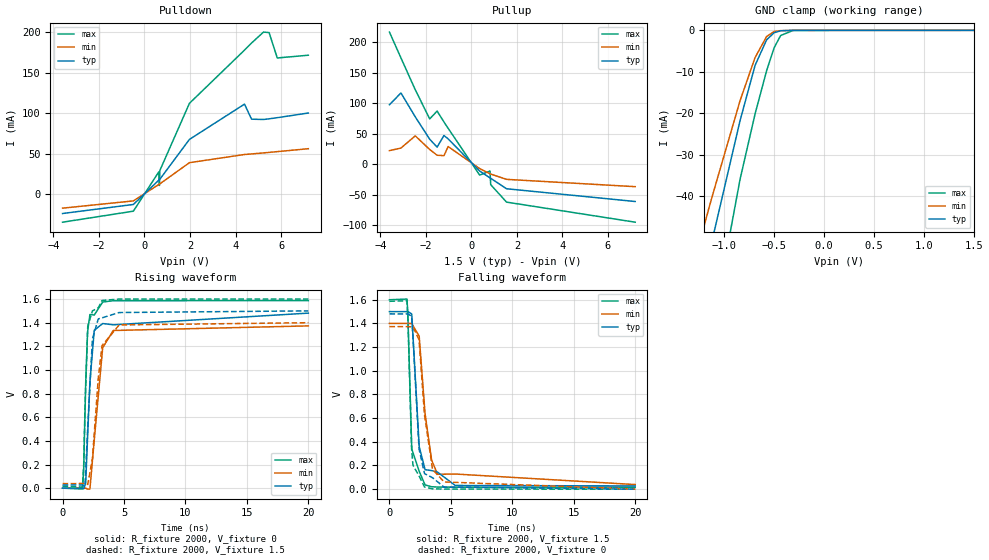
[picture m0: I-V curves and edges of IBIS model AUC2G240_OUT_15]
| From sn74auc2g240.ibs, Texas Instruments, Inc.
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[Model]   AUC2G240_OUT_15
Model_type  3-state
Enable   Active-Low
Vref =   0
Rref =   2000
Cref =   15p
Vmeas =   0.75
| variable   typ   min   max
C_comp   5.26pF   4.70pF   5.52pF
| C_pullup   4.79pF   0.02pF   13.20pF
| C_pulldown   6.36pF   5.33pF   12.83pF
| C_tri-state   5.26pF   4.70pF   5.52pF
[Temperature Range]   40   100   -40
| Ambient temperature   25   85   -40
[Voltage range]   1.5   1.4   1.6
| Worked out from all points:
|   slope of the pulldown table from 0 to 0.225 V, typ, clamps not added: 36.8 ohm
|   slope of the pullup table from 0 to 0.225 V, typ, clamps not added: 29.6 ohm
|   GND clamp passes 1 mA (typ) near -0.53 V on its own axis
|   rising waveform, R_fixture 2000, V_fixture 0: 20-80 % time 405ps typ, 635ps min, 253ps max; typ from 0 V to 1.48 V
|   falling waveform, R_fixture 2000, V_fixture 1.5: 20-80 % time 498ps typ, 792ps min, 273ps max; typ from 1.5 V to 0.027 V
|   rising waveform, R_fixture 2000, V_fixture 1.5: 20-80 % time 401ps typ, 627ps min, 250ps max; typ from 0.027 V to 1.5 V
|   falling waveform, R_fixture 2000, V_fixture 0: 20-80 % time 493ps typ, 779ps min, 271ps max; typ from 1.48 V to 0 V
[GND Clamp]
| AUC2G240_OUT_15
|   Voltage   I(typ)   I(min)   I(max)
-3.6V     -324.8mA   -272.6mA   -395.3mA
-1.51V    -93.07mA   -74.9mA    -123.7mA
-1.465V   -88.13mA   -70.8mA    -117.8mA
-1.33V    -73.37mA   -58.63mA   -100mA
-1.125V   -51.23mA   -40.54mA   -72.92mA
-840mV    -21.74mA   -16.94mA   -35.88mA
-690mV    -8.435mA   -6.553mA   -20.12mA
-575mV    -2.291mA   -1.489mA   -9.733mA
-500mV    -581.2uA   -306.5uA   -4.204mA
-435mV    -119.5uA   -65.92uA   -1.256mA
-310mV    -3.098uA   -2.805uA   -25.01uA
1.5V      385pA      7.758nA    372.5pA
[Pulldown]
| AUC2G240_OUT_15
|   Voltage   I(typ)   I(min)   I(max)
-3.6V     -23.87mA   -17.26mA   -34.61mA
-490mV    -12.71mA   -8.291mA   -20.99mA
630mV     17.4mA     12.02mA    27.68mA
655mV     18.03mA    12.44mA    10.77mA
675mV     18.52mA    12.77mA    29.29mA
1.975V    67.77mA    39mA       112.4mA
4.395V    111.4mA    49.1mA     178.2mA
4.705V    92.8mA     49.77mA    187mA
5.23V     92.39mA    51.08mA    200.5mA
5.475V    93.24mA    51.71mA    199.9mA
5.835V    94.64mA    52.66mA    168.5mA
7.2V      100.4mA    56.27mA    171.9mA
[Pullup]
| AUC2G240_OUT_15
|   Voltage   I(typ)   I(min)   I(max)
-3.6V     97.41mA    22.16mA    216.7mA
-3.095V   116.8mA    26.35mA    174.4mA
-2.465V   77.56mA    46.39mA    122mA
-1.83V    40.8mA     23.97mA    74.26mA
-1.505V   27.88mA    14.58mA    87.05mA
-1.205V   47.01mA    13.93mA    69.21mA
-1.02V    41.38mA    28.81mA    58.8mA
365mV     -11.31mA   -7.286mA   -18.05mA
820mV     -22.63mA   -15.87mA   -11.24mA
850mV     -23.26mA   -16.33mA   -33.73mA
1.545V    -40.41mA   -25mA      -62.34mA
7.2V      -61.35mA   -37.01mA   -95.3mA
[Ramp]
| AUC2G240_OUT_15
| variable   typ   min   max
dV/dt_r   0.90/4.10E-10   0.84/6.44E-10   0.96/2.55E-10
dV/dt_f   0.89/5.04E-10   0.82/7.95E-10   0.95/2.74E-10
R_load = 2000
[Rising Waveform]
| AUC2G240_OUT_15
R_fixture =   2000
C_fixture =   0
L_fixture =   0
V_fixture =   0
V_fixture_min = 0
V_fixture_max = 0
|   Time   V(typ)   V(min)   V(max)
0s        7.607nV    28.63nV    906.6pV
1.625ns   -359.9uV   463uV      -7.663mV
1.72ns    -6.097mV   596.9uV    166.8mV
1.885ns   45mV       -186.9uV   898.8mV
2.035ns   430.3mV    -8.654mV   1.322V
2.225ns   896.9mV    -8.164mV   1.469V
2.58ns    1.336V     407.6mV    1.465V
3.265ns   1.393V     1.188V     1.575V
4.125ns   1.382V     1.334V     1.586V
20ns      1.481V     1.373V     1.587V
[Falling Waveform]
| AUC2G240_OUT_15
R_fixture =   2000
C_fixture =   0
L_fixture =   0
V_fixture =   1.5
V_fixture_min = 1.4
V_fixture_max = 1.6
|   Time   V(typ)   V(min)   V(max)
0s        1.5V       1.4V       1.6V
1.43ns    1.5V       1.4V       1.606V
1.5ns     1.5V       1.4V       1.47V
1.815ns   1.48V      1.399V     339.7mV
2.42ns    361.6mV    1.293V     151.6mV
2.9ns     164.6mV    637mV      35.44mV
3.435ns   157.2mV    244.2mV    20.48mV
3.92ns    143.4mV    125.6mV    17.9mV
5.355ns   31.27mV    127.9mV    16.59mV
20ns      27.21mV    38.79mV    16.41mV
[Rising Waveform]
| AUC2G240_OUT_15
R_fixture =   2000
C_fixture =   0
L_fixture =   0
V_fixture =   1.5
V_fixture_min = 1.4
V_fixture_max = 1.6
|   Time   V(typ)   V(min)   V(max)
0s        27.17mV    38.77mV    16.4mV
1.625ns   26.8mV     39.15mV    9.101mV
1.72ns    21.75mV    39.23mV    195.8mV
1.82ns    21.42mV    39.23mV    661.1mV
2.05ns    522.3mV    30.77mV    1.37V
2.43ns    1.263V     251.1mV    1.5V
2.905ns   1.432V     929.5mV    1.526V
3.21ns    1.441V     1.206V     1.588V
4.605ns   1.486V     1.381V     1.6V
20ns      1.5V       1.4V       1.6V
[Falling Waveform]
| AUC2G240_OUT_15
R_fixture =   2000
C_fixture =   0
L_fixture =   0
V_fixture =   0
V_fixture_min = 0
V_fixture_max = 0
|   Time   V(typ)   V(min)   V(max)
0s        1.481V     1.373V     1.587V
1.43ns    1.48V      1.373V     1.592V
1.5ns     1.48V      1.373V     1.453V
1.805ns   1.461V     1.372V     338.9mV
1.915ns   1.283V     1.372V     201.4mV
2.41ns    338.9mV    1.261V     112mV
2.855ns   131.6mV    624.6mV    17.91mV
3.51ns    96.27mV    165.6mV    3.068mV
4.45ns    17.73mV    61.08mV    528.6uV
20ns      38.15uV    12.96uV    15.4uV
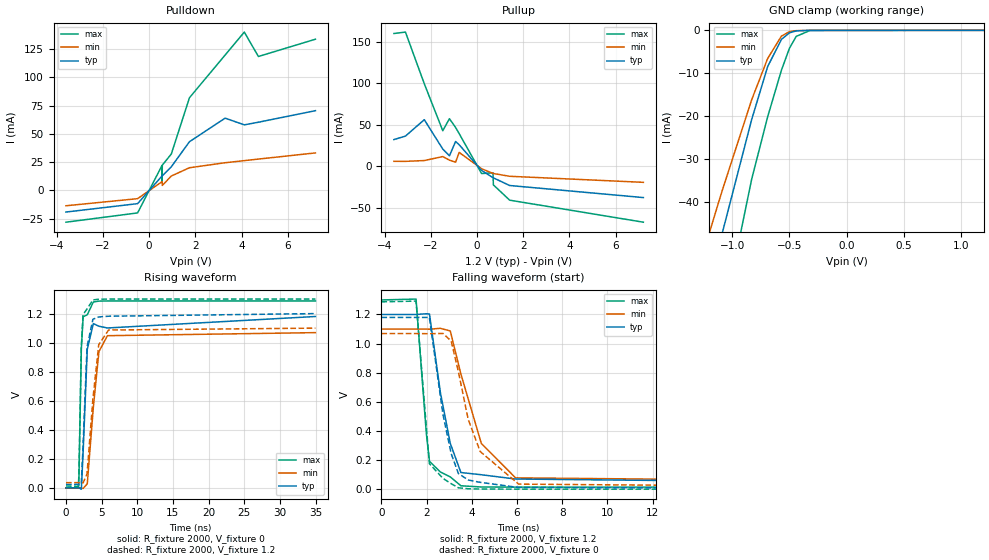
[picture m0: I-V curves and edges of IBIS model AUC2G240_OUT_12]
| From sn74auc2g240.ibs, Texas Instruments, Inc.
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[Model]   AUC2G240_OUT_12
Model_type  3-state
Enable   Active-Low
Vref =   0
Rref =   2000
Cref =   15p
Vmeas =   0.6
| variable   typ   min   max
C_comp   5.37pF   4.84pF   5.65pF
| C_pullup   4.52pF   0.82pF   9.79pF
| C_pulldown   6.19pF   5.48pF   8.81pF
| C_tri-state   5.37pF   4.84pF   5.65pF
[Temperature Range]   40   100   -40
| Ambient temperature   25   85   -40
[Voltage range]   1.2   1.1   1.3
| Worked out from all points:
|   slope of the pulldown table from 0 to 0.18 V, typ, clamps not added: 42.4 ohm
|   slope of the pullup table from 0 to 0.18 V, typ, clamps not added: 38.6 ohm
|   GND clamp passes 1 mA (typ) near -0.53 V on its own axis
|   rising waveform, R_fixture 2000, V_fixture 0: 20-80 % time 576ps typ, 1.04ns min, 320ps max; typ from 0 V to 1.18 V
|   falling waveform, R_fixture 2000, V_fixture 1.2: 20-80 % time 769ps typ, 1.25ns min, 386ps max; typ from 1.2 V to 0.024 V
|   rising waveform, R_fixture 2000, V_fixture 1.2: 20-80 % time 568ps typ, 1.03ns min, 314ps max; typ from 0.024 V to 1.2 V
|   falling waveform, R_fixture 2000, V_fixture 0: 20-80 % time 750ps typ, 1.19ns min, 381ps max; typ from 1.18 V to 0 V
[GND Clamp]
| AUC2G240_OUT_12
|   Voltage   I(typ)   I(min)   I(max)
-3.6V     -324.8mA   -272.6mA   -395.3mA
-1.455V   -87.03mA   -69.89mA   -116.5mA
-1.285V   -68.47mA   -54.61mA   -94.06mA
-1.12V    -50.69mA   -40.11mA   -72.26mA
-1.085V   -46.97mA   -37.09mA   -67.64mA
-830mV    -20.77mA   -16.17mA   -34.67mA
-690mV    -8.435mA   -6.553mA   -20.12mA
-570mV    -2.125mA   -1.36mA    -9.318mA
-500mV    -581.2uA   -306.5uA   -4.204mA
-440mV    -136.4uA   -74.2uA    -1.408mA
-320mV    -4.212uA   -3.691uA   -36.5uA
1.2V      309.5pA    7.675nA    266.7pA
[Pulldown]
| AUC2G240_OUT_12
|   Voltage   I(typ)   I(min)   I(max)
-3.6V     -19.18mA   -13.63mA   -28.17mA
-500mV    -11.75mA   -7.339mA   -19.96mA
545mV     12.46mA    7.541mA    21.58mA
550mV     12.55mA    7.59mA     7.985mA
560mV     12.73mA    7.686mA    8.172mA
570mV     12.91mA    4.373mA    22.34mA
960mV     20.87mA    12.69mA    32.2mA
1.745V    43.07mA    20.04mA    81.99mA
3.29V     63.92mA    24.45mA    119.8mA
4.12V     58mA       26.33mA    140.1mA
4.73V     60.31mA    27.69mA    118.5mA
7.2V      70.54mA    33.15mA    133.8mA
[Pullup]
| AUC2G240_OUT_12
|   Voltage   I(typ)   I(min)   I(max)
-3.6V     32.21mA    6.05mA     159.8mA
-3.1V     36.38mA    6.008mA    161.5mA
-2.285V   56.12mA    6.972mA    99.34mA
-1.485V   20.82mA    11.76mA    42.86mA
-1.195V   12.69mA    7.446mA    57.3mA
-930mV    29.91mA    5.035mA    46.79mA
-775mV    26.01mA    16.75mA    39.41mA
195mV     -4.924mA   -2.842mA   -8.652mA
690mV     -13.63mA   -8.496mA   -7.804mA
705mV     -13.8mA    -8.599mA   -22.25mA
1.41V     -23.04mA   -11.95mA   -40.67mA
7.2V      -37.56mA   -19.23mA   -67.17mA
[Ramp]
| AUC2G240_OUT_12
| variable   typ   min   max
dV/dt_r   0.72/5.81E-10   0.65/1.05E-09   0.78/3.23E-10
dV/dt_f   0.71/7.74E-10   0.64/1.26E-09   0.78/3.88E-10
R_load = 2000
[Rising Waveform]
| AUC2G240_OUT_12
R_fixture =   2000
C_fixture =   0
L_fixture =   0
V_fixture =   0
V_fixture_min = 0
V_fixture_max = 0
|   Time   V(typ)   V(min)   V(max)
0s        7.12nV     30.4nV     729.4pV
1.745ns   413.7uV    232.8uV    -1.569mV
1.82ns    433.4uV    307.8uV    79.77mV
2.155ns   -8.07mV    783.7uV    961.9mV
2.405ns   250.2mV    -3.059mV   1.178V
2.985ns   954.4mV    28.89mV    1.192V
3.835ns   1.131V     555.4mV    1.28V
4.62ns    1.113V     938.4mV    1.286V
5.81ns    1.101V     1.048V     1.287V
34.99ns   1.18V      1.069V     1.287V
[Falling Waveform]
| AUC2G240_OUT_12
R_fixture =   2000
C_fixture =   0
L_fixture =   0
V_fixture =   1.2
V_fixture_min = 1.1
V_fixture_max = 1.3
|   Time   V(typ)   V(min)   V(max)
0s        1.2V       1.1V       1.3V
1.53ns    1.2V       1.1V       1.306V
1.985ns   1.205V     1.1V       385mV
2.125ns   1.203V     1.099V     191.6mV
2.605ns   666.3mV    1.105V     118.2mV
3.045ns   314.7mV    1.087V     84.4mV
3.515ns   114.4mV    791.1mV    23.32mV
4.42ns    99.09mV    313.6mV    14.99mV
5.935ns   69.71mV    77.73mV    14.02mV
34.99ns   24mV       36.63mV    13.87mV
[Rising Waveform]
| AUC2G240_OUT_12
R_fixture =   2000
C_fixture =   0
L_fixture =   0
V_fixture =   1.2
V_fixture_min = 1.1
V_fixture_max = 1.3
|   Time   V(typ)   V(min)   V(max)
0s        23.98mV    36.63mV    13.86mV
1.735ns   24.3mV     36.8mV     10.49mV
1.82ns    24.29mV    36.85mV    105.1mV
2.135ns   23.64mV    37.05mV    956.3mV
2.39ns    285.1mV    34.29mV    1.193V
2.95ns    971.3mV    96.69mV    1.232V
3.775ns   1.161V     614.1mV    1.294V
4.595ns   1.177V     986.5mV    1.299V
5.975ns   1.182V     1.087V     1.3V
34.99ns   1.2V       1.1V       1.3V
[Falling Waveform]
| AUC2G240_OUT_12
R_fixture =   2000
C_fixture =   0
L_fixture =   0
V_fixture =   0
V_fixture_min = 0
V_fixture_max = 0
|   Time   V(typ)   V(min)   V(max)
0s        1.18V      1.069V     1.287V
1.53ns    1.18V      1.069V     1.292V
2.12ns    1.18V      1.068V     175.3mV
2.72ns    515.1mV    1.07V      74.31mV
3.085ns   244.2mV    1.018V     37.7mV
3.405ns   107.3mV    806.4mV    9.468mV
3.84ns    63.09mV    478.6mV    2.771mV
4.37ns    46.85mV    258.6mV    995.8uV
6.07ns    11.56mV    34.67mV    136.5uV
34.99ns   20.91uV    -332.8nV   8.153uV
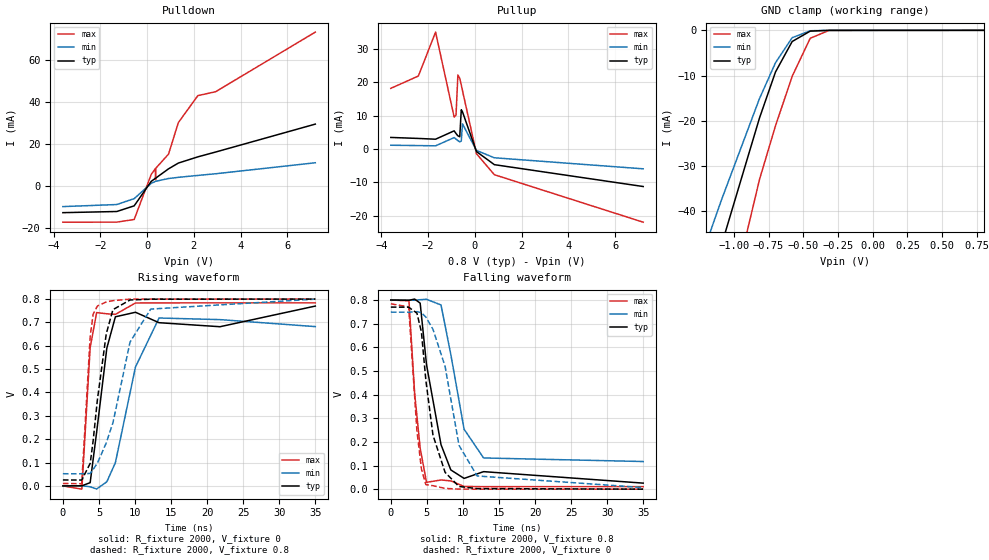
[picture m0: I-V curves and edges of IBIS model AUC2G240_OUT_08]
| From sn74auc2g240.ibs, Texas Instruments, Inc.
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[Model]   AUC2G240_OUT_08
Model_type  3-state
Enable   Active-Low
Vref =   0
Rref =   2000
Cref =   15p
Vmeas =   0.4
| variable   typ   min   max
C_comp   5.49pF   5.00pF   5.68pF
| C_pullup   5.67pF   1.14pF   7.93pF
| C_pulldown   6.37pF   5.71pF   6.83pF
| C_tri-state   5.49pF   5.00pF   5.68pF
[Temperature Range]   40   100   -40
| Ambient temperature   25   85   -40
[Voltage range]   0.8   0.8   0.8
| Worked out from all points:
|   slope of the pulldown table from 0 to 0.12 V, typ, clamps not added: 77.5 ohm
|   slope of the pullup table from 0 to 0.12 V, typ, clamps not added: 94 ohm
|   GND clamp passes 1 mA (typ) near -0.53 V on its own axis
|   rising waveform, R_fixture 2000, V_fixture 0: 20-80 % time 1.82ns typ, 2.91ns min, 908ps max; typ from 0 V to 0.77 V
|   falling waveform, R_fixture 2000, V_fixture 0.8: 20-80 % time 2.4ns typ, 2.31ns min, 1.26ns max; typ from 0.8 V to 0.026 V
|   rising waveform, R_fixture 2000, V_fixture 0.8: 20-80 % time 1.83ns typ, 3.5ns min, 867ps max; typ from 0.025 V to 0.8 V
|   falling waveform, R_fixture 2000, V_fixture 0: 20-80 % time 2.04ns typ, 2.89ns min, 1.16ns max; typ from 0.77 V to 0 V
[GND Clamp]
| AUC2G240_OUT_08
|   Voltage   I(typ)   I(min)   I(max)
-3.6V     -324.8mA   -272.6mA   -395.3mA
-1.465V   -88.13mA   -70.8mA    -117.8mA
-1.33V    -73.37mA   -58.63mA   -100mA
-1.285V   -68.47mA   -54.61mA   -94.06mA
-1.125V   -51.23mA   -40.54mA   -72.92mA
-1.09V    -47.5mA    -37.52mA   -68.3mA
-815mV    -19.32mA   -15.04mA   -32.89mA
-700mV    -9.187mA   -7.147mA   -21.07mA
-580mV    -2.465mA   -1.627mA   -10.15mA
-450mV    -176.7uA   -94.05uA   -1.748mA
-315mV    -3.612uA   -3.219uA   -30.25uA
800mV     223pA      406.9pA    175.9pA
[Pulldown]
| AUC2G240_OUT_08
|   Voltage   I(typ)   I(min)   I(max)
-3.6V     -12.84mA   -9.953mA   -17.38mA
-1.295V   -12.29mA   -8.968mA   -17.35mA
-550mV    -9.589mA   -6.157mA   -16.09mA
180mV     2.098mA    1.151mA    5.42mA
360mV     3.518mA    2.063mA    8.134mA
365mV     3.559mA    2.087mA    2.788mA
370mV     3.599mA    2.112mA    8.262mA
920mV     8.04mA     3.431mA    15.04mA
1.34V     10.79mA    3.992mA    30.07mA
2.175V    13.75mA    4.895mA    42.92mA
2.94V     16.06mA    5.706mA    44.8mA
7.2V      29.35mA    10.93mA    73.19mA
[Pullup]
| AUC2G240_OUT_08
|   Voltage   I(typ)   I(min)   I(max)
-3.6V     3.467mA    1.12mA     18.22mA
-2.42V    3.164mA    1.017mA    21.93mA
-1.685V   2.933mA    943.1uA    35.13mA
-890mV    5.445mA    3.423mA    9.571mA
-810mV    4.651mA    2.966mA    10.18mA
-730mV    3.946mA    2.515mA    22.25mA
-650mV    3.665mA    2.133mA    21.22mA
-585mV    11.79mA    2.387mA    19.26mA
-535mV    11.19mA    7.562mA    17.59mA
65mV      -779.4uA   -459.6uA   -1.427mA
830mV     -4.718mA   -2.65mA    -7.736mA
7.2V      -11.29mA   -5.969mA   -22.01mA
[Ramp]
| AUC2G240_OUT_08
| variable   typ   min   max
dV/dt_r   0.47/1.84E-09   0.46/3.46E-09   0.48/9.22E-10
dV/dt_f   0.47/2.40E-09   0.43/2.62E-09   0.48/1.26E-09
R_load = 2000
[Rising Waveform]
| AUC2G240_OUT_08
R_fixture =   2000
C_fixture =   0
L_fixture =   0
V_fixture =   0
V_fixture_min = 0
V_fixture_max = 0
|   Time   V(typ)   V(min)   V(max)
0s        8.744nV    49.66nV    546.6pV
2.63ns    451.6uV    710.7uV    -13.96mV
3.78ns    13.94mV    -3.716mV   591.9mV
4.68ns    230.6mV    -13.21mV   742.1mV
6.09ns    589.8mV    17.7mV     736.9mV
7.275ns   724mV      99.35mV    734.4mV
10.06ns   743.5mV    509mV      783.2mV
13.33ns   698.8mV    718.9mV    783.6mV
21.78ns   681.6mV    712mV      783.7mV
34.99ns   770mV      682.1mV    783.7mV
[Falling Waveform]
| AUC2G240_OUT_08
R_fixture =   2000
C_fixture =   0
L_fixture =   0
V_fixture =   0.8
V_fixture_min = 0.8
V_fixture_max = 0.8
|   Time   V(typ)   V(min)   V(max)
0s        800mV      800mV      800mV
2.515ns   798.8mV    799.6mV    796.5mV
3.3ns     804mV      799mV      406.5mV
4.07ns    786.7mV    801.3mV    173mV
4.95ns    526.3mV    803.1mV    28.95mV
6.96ns    188.2mV    779mV      38.86mV
8.32ns    81.32mV    569.4mV    34.99mV
10.16ns   45.53mV    253.4mV    11.43mV
12.86ns   74.11mV    132mV      10.68mV
34.99ns   25.55mV    116.9mV    10.61mV
[Rising Waveform]
| AUC2G240_OUT_08
R_fixture =   2000
C_fixture =   0
L_fixture =   0
V_fixture =   0.8
V_fixture_min = 0.8
V_fixture_max = 0.8
|   Time   V(typ)   V(min)   V(max)
0s        25.46mV    52.12mV    10.6mV
2.61ns    25.05mV    51.82mV    9.31mV
3.785ns   96.54mV    53.5mV     640.9mV
4.195ns   193.7mV    70.79mV    735.6mV
4.785ns   369.7mV    97.71mV    770.2mV
6.01ns    650.9mV    183.8mV    787.7mV
6.935ns   754.7mV    270.1mV    793.1mV
9.31ns    796.1mV    616.2mV    799.8mV
12.18ns   799.4mV    757.2mV    799.9mV
34.99ns   800mV      799.7mV    800mV
[Falling Waveform]
| AUC2G240_OUT_08
R_fixture =   2000
C_fixture =   0
L_fixture =   0
V_fixture =   0
V_fixture_min = 0
V_fixture_max = 0
|   Time   V(typ)   V(min)   V(max)
0s        770mV      748.6mV    783.8mV
2.475ns   769.6mV    748.4mV    771.2mV
3.62ns    744.4mV    750.8mV    246.9mV
4.245ns   664.5mV    746.5mV    85.37mV
4.86ns    459.8mV    727.8mV    19.4mV
5.845ns   228.4mV    676.1mV    14.59mV
7.525ns   71.04mV    519.1mV    3.298mV
9.45ns    11.38mV    185.6mV    244.4uV
11.96ns   2.449mV    55.82mV    65.64uV
34.99ns   54.12uV    6.747mV    12.61uV
